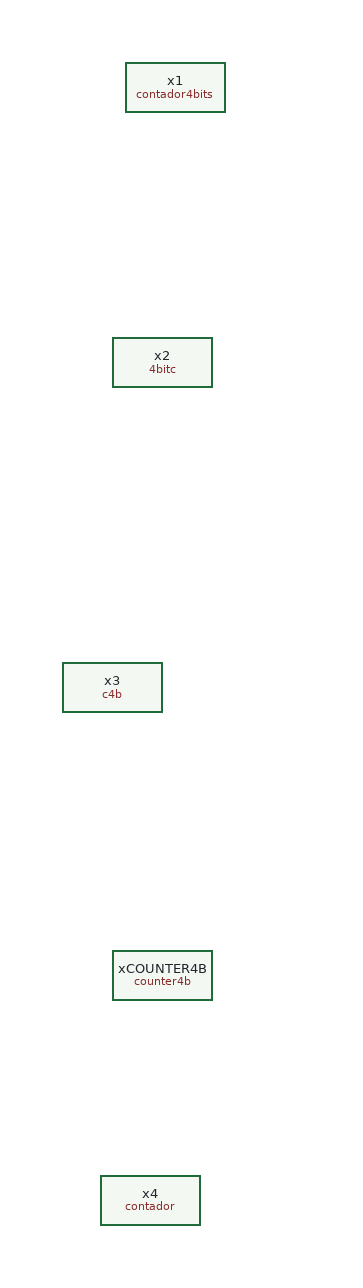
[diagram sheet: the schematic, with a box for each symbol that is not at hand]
v {xschem version=2.9.9 file_version=1.2 }
G {}
K {}
V {}
S {}
E {}
C {/home/eamta/caravel_eamta_2021/track_vlsi/lapi-fernandez/sch/contador4bits.sym} 190 -340 0 0 {name=x1}
C {/home/eamta/caravel_eamta_2021/track_vlsi/ledesma/sch/4bitc.sym} 180 -120 0 0 {name=x2}
C {/home/eamta/caravel_eamta_2021/track_vlsi/martinez-sapriza/sch/c4b.sym} 140 140 0 0 {name=x3}
C {/home/eamta/caravel_eamta_2021/track_vlsi/scandaliaris/sch/counter4b.sym} 180 370 0 0 {name=xCOUNTER4B VSS=VSS VDD=VDD}
C {/home/eamta/caravel_eamta_2021/track_vlsi/somoza/sch/contador.sym} 170 550 0 0 {name=x4}
